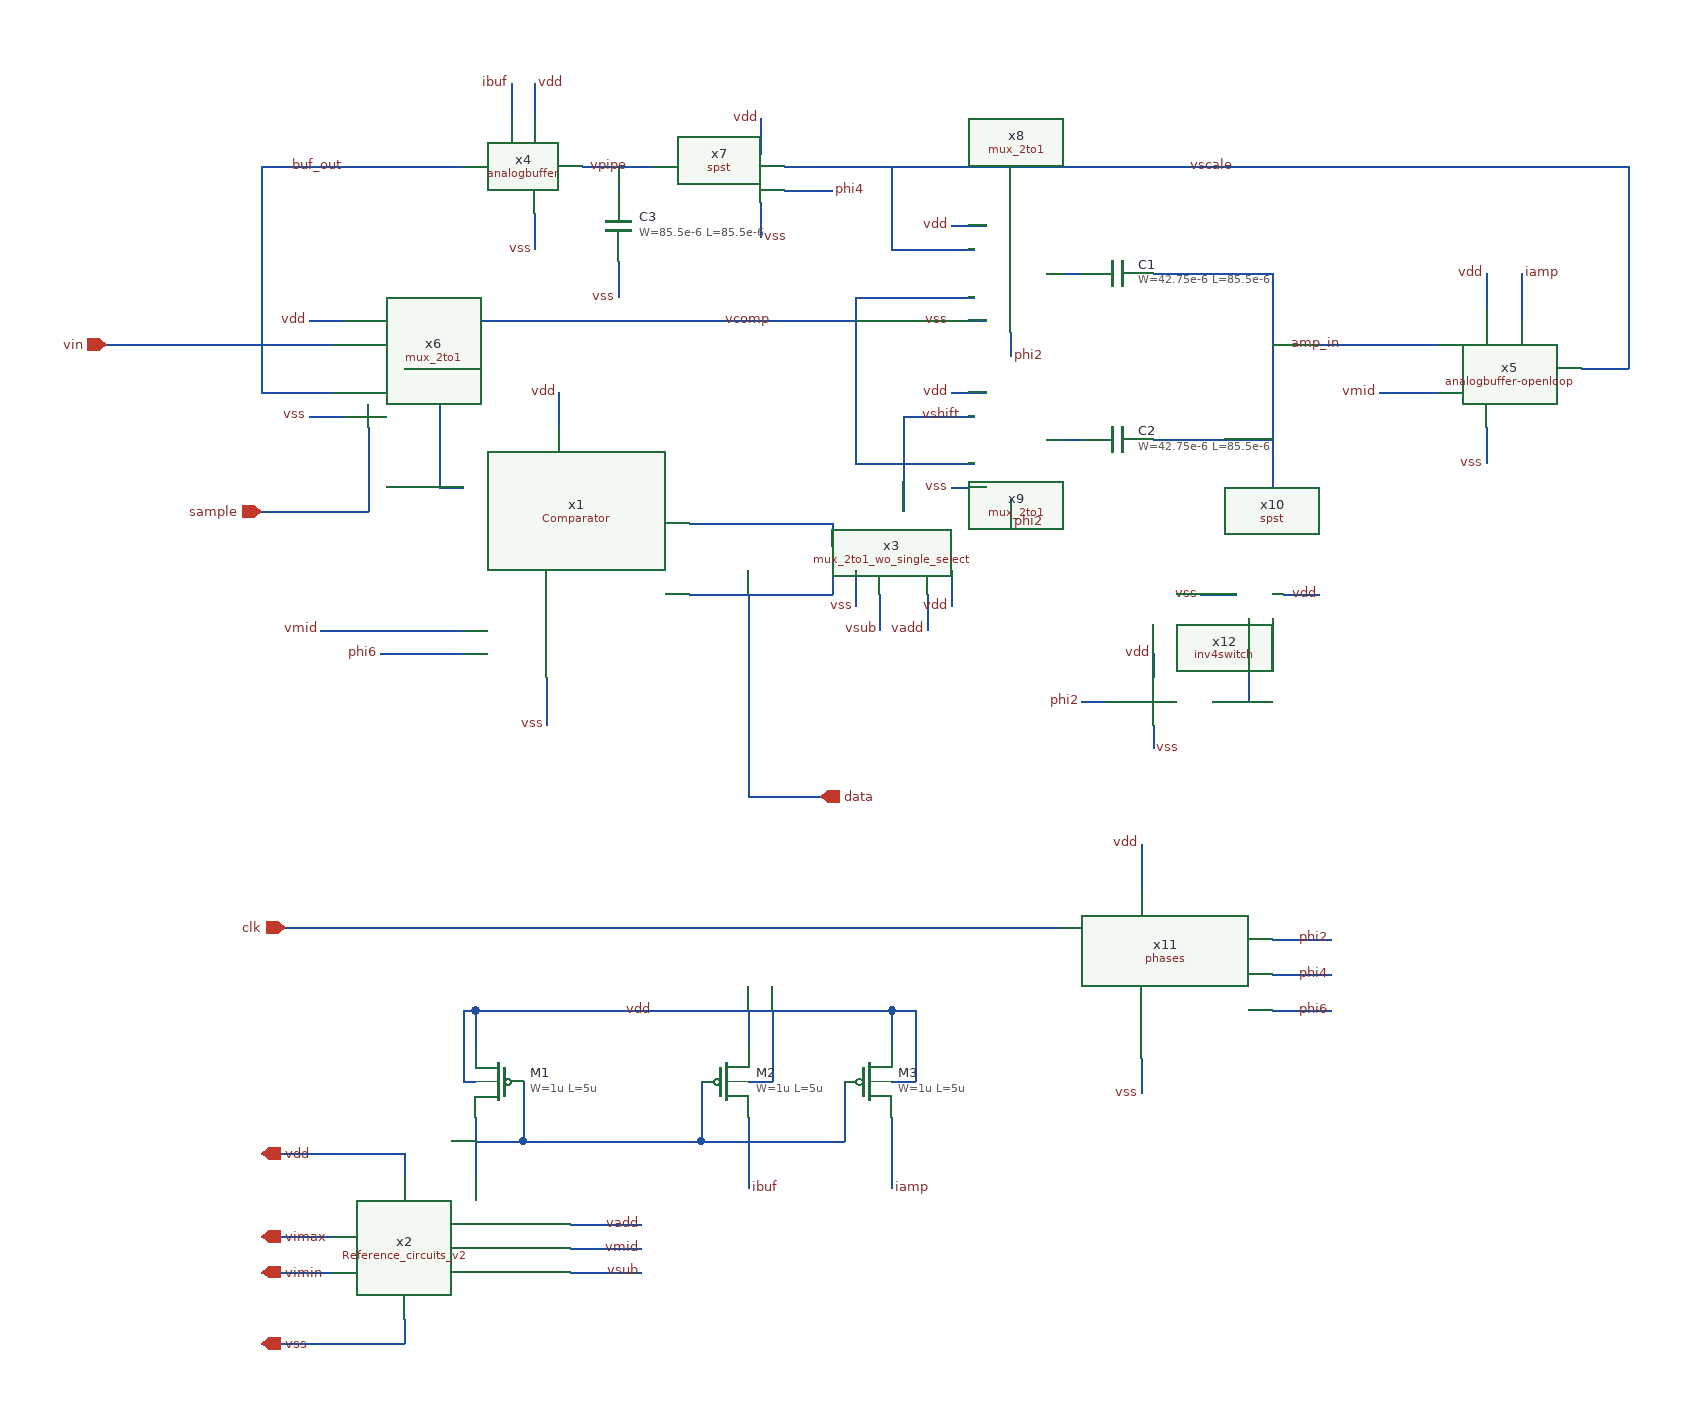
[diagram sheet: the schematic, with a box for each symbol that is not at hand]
v {xschem version=3.4.8RC file_version=1.3}
G {}
K {}
V {}
S {}
F {}
E {}
N 100 -150 220 -150 {lab=vdd}
N 220 -150 220 -130 {lab=vdd}
N 100 10 220 10 {lab=vss}
N 220 -10 220 10 {lab=vss}
N 100 -80 160 -80 {lab=vimax}
N 100 -50 160 -50 {lab=vimin}
N 360 -90 420 -90 {lab=vadd}
N 360 -70 420 -70 {lab=vmid}
N 360 -50 420 -50 {lab=vsub}
N 460 -680 580 -680 {lab=#net1}
N 580 -680 580 -660 {lab=#net1}
N 460 -620 580 -620 {lab=data}
N 580 -650 580 -620 {lab=data}
N 620 -620 620 -590 {lab=vsub}
N 660 -620 660 -590 {lab=vadd}
N -30 -830 160 -830 {lab=vin}
N 370 -980 430 -980 {lab=vpipe}
N 400 -980 400 -960 {lab=vpipe}
N 250 -710 270 -710 {lab=vcomp}
N 220 -810 250 -810 {lab=vcomp}
N 150 -590 270 -590 {lab=vmid}
N 100 -980 270 -980 {lab=buf_out}
N 760 -750 790 -750 {lab=#net2}
N 760 -890 790 -890 {lab=#net3}
N 1040 -790 1090 -790 {lab=vmid}
N 850 -750 950 -750 {lab=amp_in}
N 850 -890 950 -890 {lab=amp_in}
N 950 -890 950 -710 {lab=amp_in}
N 950 -830 1090 -830 {lab=amp_in}
N 1210 -810 1250 -810 {lab=vscale}
N 640 -980 1250 -980 {lab=vscale}
N 540 -980 640 -980 {lab=vscale}
N 1250 -980 1250 -810 {lab=vscale}
N 400 -900 400 -870 {lab=vss}
N 330 -1050 330 -1020 {lab=vdd}
N 330 -940 330 -910 {lab=vss}
N 1130 -890 1130 -860 {lab=vdd}
N 1130 -760 1130 -730 {lab=vss}
N 250 -810 250 -710 {lab=vcomp}
N 350 -790 350 -760 {lab=vdd}
N 340 -550 340 -510 {lab=vss}
N 950 -600 950 -570 {lab=vmid}
N 600 -640 600 -610 {lab=vss}
N 680 -640 680 -610 {lab=vdd}
N 680 -710 710 -710 {lab=vss}
N 680 -790 710 -790 {lab=vdd}
N 680 -850 710 -850 {lab=vss}
N 680 -930 710 -930 {lab=vdd}
N 520 -1020 520 -990 {lab=vdd}
N 520 -950 520 -920 {lab=vss}
N 960 -620 990 -620 {lab=vdd}
N 890 -620 920 -620 {lab=vss}
N 250 -850 250 -810 {lab=vcomp}
N 140 -770 170 -770 {lab=vss}
N 140 -850 170 -850 {lab=vdd}
N 510 -620 510 -450 {lab=data}
N 510 -450 570 -450 {lab=data}
N 100 -690 190 -690 {lab=sample}
N 190 -760 190 -690 {lab=sample}
N 840 -410 840 -370 {lab=vdd}
N 840 -230 840 -200 {lab=vss}
N 120 -340 590 -340 {lab=clk}
N 950 -330 1000 -330 {lab=phi2}
N 950 -300 1000 -300 {lab=phi4}
N 950 -270 1000 -270 {lab=phi6}
N 730 -840 730 -820 {lab=phi2}
N 730 -700 730 -680 {lab=phi2}
N 930 -600 930 -580 {lab=#net4}
N 590 -340 770 -340 {lab=clk}
N 280 -270 280 -240 {lab=vdd}
N 280 -270 630 -270 {lab=vdd}
N 630 -270 630 -240 {lab=vdd}
N 510 -270 510 -240 {lab=vdd}
N 510 -210 530 -210 {lab=vdd}
N 530 -270 530 -210 {lab=vdd}
N 630 -210 650 -210 {lab=vdd}
N 650 -270 650 -210 {lab=vdd}
N 630 -270 650 -270 {lab=vdd}
N 320 -210 320 -160 {lab=#net5}
N 320 -160 470 -160 {lab=#net5}
N 470 -210 470 -160 {lab=#net5}
N 470 -160 590 -160 {lab=#net5}
N 590 -210 590 -160 {lab=#net5}
N 510 -180 510 -120 {lab=ibuf}
N 630 -180 630 -120 {lab=iamp}
N 280 -180 280 -130 {lab=#net5}
N 270 -210 280 -210 {lab=vdd}
N 270 -270 270 -210 {lab=vdd}
N 270 -270 280 -270 {lab=vdd}
N 1160 -890 1160 -850 {lab=iamp}
N 310 -1050 310 -1020 {lab=ibuf}
N 540 -960 580 -960 {lab=phi4}
N 200 -570 270 -570 {lab=phi6}
N 280 -160 320 -160 {lab=#net5}
N 250 -850 600 -850 {lab=vcomp}
N 640 -770 640 -690 {lab=vshift}
N 640 -770 700 -770 {lab=vshift}
N 600 -870 700 -870 {lab=vcomp}
N 600 -870 600 -730 {lab=vcomp}
N 600 -730 700 -730 {lab=vcomp}
N 630 -910 700 -910 {lab=vscale}
N 630 -980 630 -910 {lab=vscale}
N 790 -530 810 -530 {lab=phi2}
N 900 -530 930 -530 {lab=#net4}
N 930 -580 930 -530 {lab=#net4}
N 850 -570 850 -550 {lab=vdd}
N 850 -510 850 -490 {lab=vss}
N 100 -790 160 -790 {lab=buf_out}
N 100 -980 100 -790 {lab=buf_out}
C {ADC/Comparator/Comparator.sym} 420 -650 0 0 {name=x1}
C {title.sym} 110 120 0 0 {name=l1 author="Tobias Huber"}
C {ADC/Reference/Reference_circuits_v2.sym} 160 -50 0 0 {name=x2}
C {iopin.sym} 100 -150 0 1 {name=p1 lab=vdd}
C {iopin.sym} 100 10 0 1 {name=p2 lab=vss}
C {iopin.sym} 100 -50 0 1 {name=p3 lab=vimin}
C {iopin.sym} 100 -80 0 1 {name=p4 lab=vimax}
C {lab_wire.sym} 420 -90 0 0 {name=p5 sig_type=std_logic lab=vadd}
C {lab_wire.sym} 420 -70 0 0 {name=p6 sig_type=std_logic lab=vmid}
C {lab_wire.sym} 420 -50 0 0 {name=p7 sig_type=std_logic lab=vsub}
C {symbols/cap_mim_2f0fF.sym} 400 -930 0 0 {name=C3
W=85.5e-6
L=85.5e-6
model=cap_mim_2f0fF
spiceprefix=X
m=1}
C {symbols/cap_mim_2f0fF.sym} 820 -890 1 0 {name=C1
W=42.75e-6
L=85.5e-6
model=cap_mim_2f0fF
spiceprefix=X
m=1}
C {symbols/cap_mim_2f0fF.sym} 820 -750 1 0 {name=C2
W=42.75e-6
L=85.5e-6
model=cap_mim_2f0fF
spiceprefix=X
m=1}
C {ADC/switching/mux_2to1_wo_single_select.sym} 620 -620 1 1 {name=x3}
C {lab_wire.sym} 660 -590 3 0 {name=p8 sig_type=std_logic lab=vadd}
C {lab_wire.sym} 620 -590 3 0 {name=p10 sig_type=std_logic lab=vsub}
C {ADC/switching/mux_2to1.sym} 150 -790 0 0 {name=x6}
C {ipin.sym} -30 -830 0 0 {name=p9 lab=vin}
C {ADC/switching/spst.sym} 380 -960 0 1 {name=x7}
C {ADC/switching/mux_2to1.sym} 690 -870 0 0 {name=x8}
C {ADC/switching/mux_2to1.sym} 690 -730 0 0 {name=x9}
C {ADC/analogbuffer/analogbuffer.sym} 370 -980 0 1 {name=x4}
C {ADC/switching/spst.sym} 930 -760 1 1 {name=x10}
C {lab_wire.sym} 150 -590 0 0 {name=p11 sig_type=std_logic lab=vmid}
C {ADC/analogbuffer/analogbuffer-openloop.sym} 1090 -790 0 0 {name=x5}
C {lab_wire.sym} 1040 -790 0 0 {name=p12 sig_type=std_logic lab=vmid}
C {lab_wire.sym} 400 -870 0 0 {name=p13 sig_type=std_logic lab=vss}
C {lab_wire.sym} 330 -910 0 0 {name=p14 sig_type=std_logic lab=vss}
C {lab_wire.sym} 330 -1050 0 1 {name=p15 sig_type=std_logic lab=vdd}
C {lab_wire.sym} 1130 -730 0 0 {name=p16 sig_type=std_logic lab=vss}
C {lab_wire.sym} 1130 -890 0 0 {name=p17 sig_type=std_logic lab=vdd}
C {lab_wire.sym} 350 -790 0 0 {name=p18 sig_type=std_logic lab=vdd}
C {lab_wire.sym} 340 -510 0 0 {name=p19 sig_type=std_logic lab=vss}
C {lab_wire.sym} 950 -570 3 0 {name=p20 sig_type=std_logic lab=vmid}
C {lab_wire.sym} 600 -610 3 0 {name=p21 sig_type=std_logic lab=vss}
C {lab_wire.sym} 680 -610 3 0 {name=p22 sig_type=std_logic lab=vdd}
C {lab_wire.sym} 680 -710 2 1 {name=p23 sig_type=std_logic lab=vss}
C {lab_wire.sym} 680 -790 0 0 {name=p24 sig_type=std_logic lab=vdd}
C {lab_wire.sym} 680 -850 2 1 {name=p25 sig_type=std_logic lab=vss}
C {lab_wire.sym} 680 -930 0 0 {name=p26 sig_type=std_logic lab=vdd}
C {lab_wire.sym} 520 -1020 0 0 {name=p27 sig_type=std_logic lab=vdd}
C {lab_wire.sym} 520 -920 0 1 {name=p28 sig_type=std_logic lab=vss}
C {lab_wire.sym} 990 -620 1 0 {name=p29 sig_type=std_logic lab=vdd}
C {lab_wire.sym} 890 -620 1 0 {name=p30 sig_type=std_logic lab=vss}
C {lab_wire.sym} 410 -980 0 0 {name=p31 sig_type=std_logic lab=vpipe}
C {lab_wire.sym} 920 -980 0 0 {name=p32 sig_type=std_logic lab=vscale}
C {lab_wire.sym} 530 -850 0 0 {name=p33 sig_type=std_logic lab=vcomp}
C {lab_wire.sym} 140 -770 2 1 {name=p34 sig_type=std_logic lab=vss}
C {lab_wire.sym} 140 -850 2 1 {name=p35 sig_type=std_logic lab=vdd}
C {opin.sym} 570 -450 0 0 {name=p36 lab=data}
C {ipin.sym} 100 -690 0 0 {name=p37 lab=sample}
C {ADC/delay/phases.sym} 770 -340 0 0 {name=x11}
C {lab_wire.sym} 840 -410 0 0 {name=p38 sig_type=std_logic lab=vdd}
C {lab_wire.sym} 840 -200 0 0 {name=p39 sig_type=std_logic lab=vss}
C {ipin.sym} 120 -340 0 0 {name=p40 lab=clk}
C {lab_wire.sym} 1000 -330 0 0 {name=p41 sig_type=std_logic lab=phi2}
C {lab_wire.sym} 1000 -300 0 0 {name=p42 sig_type=std_logic lab=phi4}
C {lab_wire.sym} 1000 -270 0 0 {name=p43 sig_type=std_logic lab=phi6}
C {lab_wire.sym} 730 -820 2 0 {name=p44 sig_type=std_logic lab=phi2}
C {lab_wire.sym} 730 -680 2 0 {name=p45 sig_type=std_logic lab=phi2}
C {lab_wire.sym} 790 -530 2 1 {name=p46 sig_type=std_logic lab=phi2}
C {lab_wire.sym} 690 -770 2 1 {name=p47 sig_type=std_logic lab=vshift}
C {symbols/pfet_03v3.sym} 300 -210 0 1 {name=M1
L=5u
W=1u
nf=1
m=1
ad="'int((nf+1)/2) * W/nf * 0.18u'"
pd="'2*int((nf+1)/2) * (W/nf + 0.18u)'"
as="'int((nf+2)/2) * W/nf * 0.18u'"
ps="'2*int((nf+2)/2) * (W/nf + 0.18u)'"
nrd="'0.18u / W'" nrs="'0.18u / W'"
sa=0 sb=0 sd=0
model=pfet_03v3
spiceprefix=X
}
C {symbols/pfet_03v3.sym} 490 -210 0 0 {name=M2
L=5u
W=1u
nf=1
m=1
ad="'int((nf+1)/2) * W/nf * 0.18u'"
pd="'2*int((nf+1)/2) * (W/nf + 0.18u)'"
as="'int((nf+2)/2) * W/nf * 0.18u'"
ps="'2*int((nf+2)/2) * (W/nf + 0.18u)'"
nrd="'0.18u / W'" nrs="'0.18u / W'"
sa=0 sb=0 sd=0
model=pfet_03v3
spiceprefix=X
}
C {symbols/pfet_03v3.sym} 610 -210 0 0 {name=M3
L=5u
W=1u
nf=1
m=1
ad="'int((nf+1)/2) * W/nf * 0.18u'"
pd="'2*int((nf+1)/2) * (W/nf + 0.18u)'"
as="'int((nf+2)/2) * W/nf * 0.18u'"
ps="'2*int((nf+2)/2) * (W/nf + 0.18u)'"
nrd="'0.18u / W'" nrs="'0.18u / W'"
sa=0 sb=0 sd=0
model=pfet_03v3
spiceprefix=X
}
C {lab_wire.sym} 510 -120 2 0 {name=p48 sig_type=std_logic lab=ibuf}
C {lab_wire.sym} 630 -120 2 0 {name=p49 sig_type=std_logic lab=iamp}
C {lab_wire.sym} 430 -270 0 0 {name=p50 sig_type=std_logic lab=vdd}
C {lab_wire.sym} 1160 -890 0 1 {name=p51 sig_type=std_logic lab=iamp}
C {lab_wire.sym} 310 -1050 0 0 {name=p52 sig_type=std_logic lab=ibuf}
C {lab_wire.sym} 580 -960 2 0 {name=p53 sig_type=std_logic lab=phi4}
C {lab_wire.sym} 200 -570 0 0 {name=p54 sig_type=std_logic lab=phi6}
C {lab_wire.sym} 1010 -830 0 0 {name=p55 sig_type=std_logic lab=amp_in}
C {lab_wire.sym} 170 -980 0 0 {name=p56 sig_type=std_logic lab=buf_out}
C {ADC/switching/inv4switch.sym} 930 -530 0 0 {name=x12}
C {lab_wire.sym} 850 -490 2 0 {name=p57 sig_type=std_logic lab=vss}
C {lab_wire.sym} 850 -570 0 0 {name=p58 sig_type=std_logic lab=vdd}
